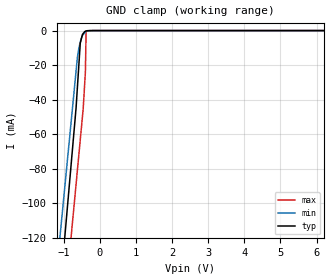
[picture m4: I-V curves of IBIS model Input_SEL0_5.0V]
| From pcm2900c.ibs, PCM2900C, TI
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[Model] Input_SEL0_5.0V
Model_type Input
Vinl  = 800.000mV
Vinh  = 2.00000V
C_comp  2.00000pF 2.00000pF 2.00000pF
| variable   typ   min   max
[Voltage Range]   5.00000V  4.50000V  5.50000V
[POWER Clamp Reference]  5.00000V  4.50000V  5.50000V
[GND Clamp Reference]   0.00000V  0.00000V  0.00000V
[Temperature Range]   25   85   -25
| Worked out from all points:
|   GND clamp passes 1 mA (typ) near -0.44 V on its own axis
[GND Clamp]
-5V       -1.086A    -958.5mA   -1.053A
-659mV    -44.76mA   -23.41mA   -89.04mA
-623.5mV  -33.32mA   -15.77mA   -81.16mA
-582.7mV  -20.16mA   -10.09mA   -72.1mA
-542.3mV  -7.134mA   -6.607mA   -63.13mA
-522.1mV  -5.472mA   -4.867mA   -58.65mA
-481.6mV  -2.142mA   -2.748mA   -49.66mA
-461.7mV  -1.61mA    -2.226mA   -45.23mA
-400.6mV  -319.8uA   -632.8uA   -23.89mA
-380.7mV  -116.8uA   -386.6uA   -115.3uA
-159.9mV  93.03uA    84.25uA    94.29uA
10V       93.03uA    84.25uA    96.59uA
[POWER Clamp]
| Voltage   I(typ)   I(min)   I(max)
-5.5V     0A         0A         0A
-5.4V     0A         0A         0A
-5.3V     0A         0A         0A
11V       0A         0A         0A
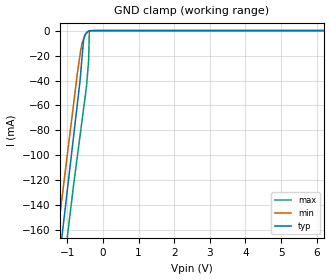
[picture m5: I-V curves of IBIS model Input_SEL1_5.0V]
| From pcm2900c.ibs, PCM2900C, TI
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[Model] Input_SEL1_5.0V
Model_type Input
Vinl  = 800.000mV
Vinh  = 2.00000V
C_comp  2.00000pF 2.00000pF 2.00000pF
| variable   typ   min   max
[Voltage Range]   5.00000V  4.50000V  5.50000V
[POWER Clamp Reference]  5.00000V  4.50000V  5.50000V
[GND Clamp Reference]   0.00000V  0.00000V  0.00000V
[Temperature Range]   25   85   -25
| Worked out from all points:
|   GND clamp passes 1 mA (typ) near -0.44 V on its own axis
[GND Clamp]
-5V       -1.113A    -1.026A    -1.117A
-820.9mV  -84.3mA    -58.32mA   -123.3mA
-719.5mV  -59.35mA   -34.85mA   -101.3mA
-643.8mV  -40.71mA   -19.91mA   -84.75mA
-623.5mV  -34.02mA   -15.92mA   -80.34mA
-582.7mV  -20.54mA   -10.12mA   -71.46mA
-542.3mV  -7.2mA     -6.566mA   -62.66mA
-502mV    -3.275mA   -3.87mA    -53.87mA
-461.8mV  -1.716mA   -2.038mA   -45.12mA
-400.7mV  -381uA     -611.7uA   -24.05mA
-380.8mV  -114.6uA   -405uA     -155.8uA
10V       102.3uA    81.83uA    86.08uA
[POWER Clamp]
| Voltage   I(typ)   I(min)   I(max)
-5.5V     0A         0A         0A
-5.4V     0A         0A         0A
-5.3V     0A         0A         0A
11V       0A         0A         0A
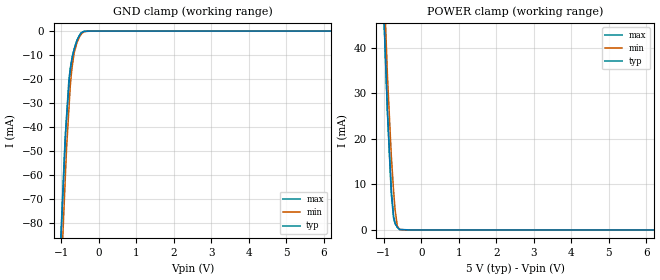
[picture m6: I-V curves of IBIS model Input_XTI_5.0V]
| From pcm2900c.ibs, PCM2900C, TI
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[Model] Input_XTI_5.0V
Model_type Input
Vinl  = 900.000mV
Vinh  = 2.52000V
C_comp  2.00000pF 2.00000pF 2.00000pF
| variable   typ   min   max
[Voltage Range]   5.00000V  4.50000V  5.50000V
[POWER Clamp Reference]  5.00000V  4.50000V  5.50000V
[GND Clamp Reference]   0.00000V  0.00000V  0.00000V
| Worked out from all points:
|   GND clamp passes 1 mA (typ) near -0.49 V on its own axis
|   POWER clamp passes 1 mA (typ) near -0.67 V on its own axis
[GND Clamp]
-5V       -1.501A    -1.572A    -1.531A
-901.2mV  -48.31mA   -63.77mA   -45.37mA
-881.1mV  -41.18mA   -56.38mA   -40.48mA
-861.1mV  -36.71mA   -49.02mA   -35.61mA
-800.5mV  -23.13mA   -33.12mA   -20.84mA
-780.4mV  -18.62mA   -27.84mA   -18.09mA
-760.1mV  -16.34mA   -22.52mA   -15.31mA
-719.5mV  -11.78mA   -15.74mA   -11.67mA
-659mV    -7.552mA   -9.171mA   -7.612mA
-582.7mV  -3.994mA   -4.677mA   -3.835mA
-421mV    -261.4uA   -498.2uA   -159.5uA
10V       103.2uA    76uA       106.5uA
[POWER Clamp]
-5V       925.1mA    944.4mA    939.7mA
-1.079V   64.66mA    72.79mA    64.78mA
-901.9mV  25.92mA    33.54mA    25.38mA
-800.9mV  8.984mA    16.35mA    7.908mA
-739.5mV  2.989mA    8.553mA    2.587mA
-699.6mV  1.522mA    4.415mA    1.373mA
-638.9mV  578.2uA    825.2uA    604.1uA
-578.1mV  120.9uA    119.7uA    54.61uA
10V       0A         0A         0A
